VERSION 5.7 ;
  NOWIREEXTENSIONATPIN ON ;
  DIVIDERCHAR "/" ;
  BUSBITCHARS "[]" ;
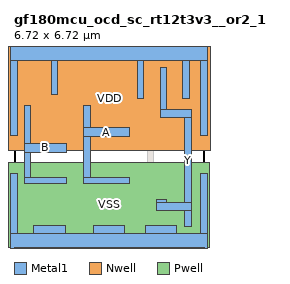
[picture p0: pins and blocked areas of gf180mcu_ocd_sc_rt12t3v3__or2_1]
MACRO gf180mcu_ocd_sc_rt12t3v3__or2_1
  CLASS CORE ;
  FOREIGN gf180mcu_ocd_sc_rt12t3v3__or2_1 ;
  ORIGIN 0.000 0.000 ;
  SIZE 6.720 BY 6.720 ;
  SYMMETRY X Y ;
  SITE unithd ;
  PIN A
    DIRECTION INPUT ;
    USE SIGNAL ;
    ANTENNAGATEAREA 1.672300 ;
    PORT
      LAYER Metal1 ;
        RECT 2.465 4.050 2.695 4.825 ;
        RECT 2.465 3.725 4.095 4.050 ;
        RECT 2.465 2.285 2.695 3.725 ;
        RECT 2.465 2.055 4.095 2.285 ;
    END
  END A
  PIN B
    DIRECTION INPUT ;
    USE SIGNAL ;
    ANTENNAGATEAREA 1.672300 ;
    PORT
      LAYER Metal1 ;
        RECT 0.370 3.490 0.600 4.825 ;
        RECT 0.370 3.160 1.870 3.490 ;
        RECT 0.370 2.285 0.600 3.160 ;
        RECT 0.370 2.055 1.870 2.285 ;
    END
  END B
  PIN Y
    DIRECTION OUTPUT ;
    USE SIGNAL ;
    ANTENNADIFFAREA 0.976900 ;
    PORT
      LAYER Metal1 ;
        RECT 5.165 4.670 5.395 6.180 ;
        RECT 5.165 4.410 6.290 4.670 ;
        RECT 5.030 1.380 5.410 1.500 ;
        RECT 6.030 1.380 6.290 4.410 ;
        RECT 5.030 1.120 6.290 1.380 ;
        RECT 6.030 0.535 6.290 1.120 ;
    END
  END Y
  PIN VDD
    DIRECTION INOUT ;
    USE POWER ;
    SHAPE ABUTMENT ;
    PORT
      LAYER Nwell ;
        RECT -0.610 3.245 7.330 7.330 ;
      LAYER Metal1 ;
        RECT -0.115 6.420 6.835 7.020 ;
        RECT -0.115 3.750 0.115 6.420 ;
        RECT 1.325 5.205 1.555 6.420 ;
        RECT 4.365 5.060 4.595 6.420 ;
        RECT 5.965 5.065 6.195 6.420 ;
        RECT 6.605 3.750 6.835 6.420 ;
    END
  END VDD
  PIN VSS
    DIRECTION INOUT ;
    USE GROUND ;
    SHAPE ABUTMENT ;
    PORT
      LAYER Pwell ;
        RECT -0.180 -0.180 6.900 2.815 ;
        RECT 0.000 -0.300 6.720 -0.180 ;
      LAYER Metal1 ;
        RECT -0.115 0.300 0.115 2.410 ;
        RECT 0.700 0.300 1.810 0.585 ;
        RECT 2.820 0.300 3.900 0.585 ;
        RECT 4.650 0.300 5.760 0.585 ;
        RECT 6.605 0.300 6.835 2.410 ;
        RECT -0.115 -0.300 6.835 0.300 ;
    END
  END VSS
  OBS
      LAYER Metal1 ;
        RECT 0.525 5.290 0.755 6.190 ;
        RECT 2.125 5.960 3.955 6.190 ;
        RECT 2.125 5.290 2.355 5.960 ;
        RECT 0.525 5.060 1.060 5.290 ;
        RECT 0.830 4.975 1.060 5.060 ;
        RECT 1.785 5.060 2.355 5.290 ;
        RECT 1.785 4.975 2.015 5.060 ;
        RECT 0.830 4.745 2.015 4.975 ;
        RECT 2.925 4.740 3.155 5.730 ;
        RECT 3.725 5.055 3.955 5.960 ;
        RECT 4.705 4.740 4.935 4.825 ;
        RECT 2.925 4.510 4.935 4.740 ;
        RECT 4.705 2.285 4.935 4.510 ;
        RECT 4.570 2.055 5.760 2.285 ;
        RECT 4.570 1.425 4.800 2.055 ;
        RECT 1.080 1.195 4.800 1.425 ;
  END
END gf180mcu_ocd_sc_rt12t3v3__or2_1
END LIBRARY

